VERSION 5.7 ;
BUSBITCHARS "[]" ;
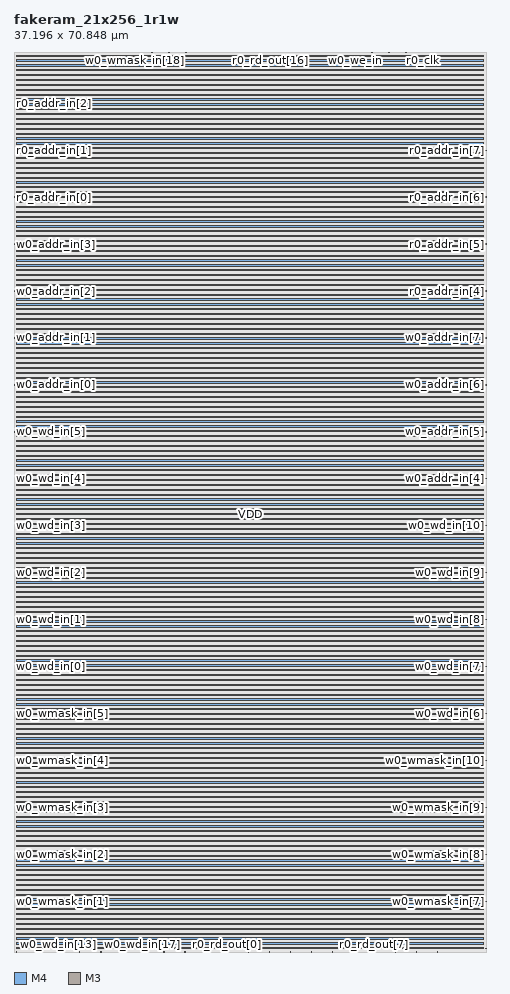
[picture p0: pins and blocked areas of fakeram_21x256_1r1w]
MACRO fakeram_21x256_1r1w
  FOREIGN fakeram_21x256_1r1w 0 0 ;
  SYMMETRY X Y R90 ;
  SIZE 37.196 BY 70.848 ;
  CLASS BLOCK ;
  PIN w0_wmask_in[0]
    DIRECTION INPUT ;
    USE SIGNAL ;
    SHAPE ABUTMENT ;
    PORT
      LAYER M4 ;
      RECT 0.000 0.276 0.072 0.300 ;
    END
  END w0_wmask_in[0]
  PIN w0_wmask_in[1]
    DIRECTION INPUT ;
    USE SIGNAL ;
    SHAPE ABUTMENT ;
    PORT
      LAYER M4 ;
      RECT 0.000 3.972 0.072 3.996 ;
    END
  END w0_wmask_in[1]
  PIN w0_wmask_in[2]
    DIRECTION INPUT ;
    USE SIGNAL ;
    SHAPE ABUTMENT ;
    PORT
      LAYER M4 ;
      RECT 0.000 7.668 0.072 7.692 ;
    END
  END w0_wmask_in[2]
  PIN w0_wmask_in[3]
    DIRECTION INPUT ;
    USE SIGNAL ;
    SHAPE ABUTMENT ;
    PORT
      LAYER M4 ;
      RECT 0.000 11.364 0.072 11.388 ;
    END
  END w0_wmask_in[3]
  PIN w0_wmask_in[4]
    DIRECTION INPUT ;
    USE SIGNAL ;
    SHAPE ABUTMENT ;
    PORT
      LAYER M4 ;
      RECT 0.000 15.060 0.072 15.084 ;
    END
  END w0_wmask_in[4]
  PIN w0_wmask_in[5]
    DIRECTION INPUT ;
    USE SIGNAL ;
    SHAPE ABUTMENT ;
    PORT
      LAYER M4 ;
      RECT 0.000 18.756 0.072 18.780 ;
    END
  END w0_wmask_in[5]
  PIN w0_wmask_in[6]
    DIRECTION INPUT ;
    USE SIGNAL ;
    SHAPE ABUTMENT ;
    PORT
      LAYER M4 ;
      RECT 37.124 0.276 37.196 0.300 ;
    END
  END w0_wmask_in[6]
  PIN w0_wmask_in[7]
    DIRECTION INPUT ;
    USE SIGNAL ;
    SHAPE ABUTMENT ;
    PORT
      LAYER M4 ;
      RECT 37.124 3.972 37.196 3.996 ;
    END
  END w0_wmask_in[7]
  PIN w0_wmask_in[8]
    DIRECTION INPUT ;
    USE SIGNAL ;
    SHAPE ABUTMENT ;
    PORT
      LAYER M4 ;
      RECT 37.124 7.668 37.196 7.692 ;
    END
  END w0_wmask_in[8]
  PIN w0_wmask_in[9]
    DIRECTION INPUT ;
    USE SIGNAL ;
    SHAPE ABUTMENT ;
    PORT
      LAYER M4 ;
      RECT 37.124 11.364 37.196 11.388 ;
    END
  END w0_wmask_in[9]
  PIN w0_wmask_in[10]
    DIRECTION INPUT ;
    USE SIGNAL ;
    SHAPE ABUTMENT ;
    PORT
      LAYER M4 ;
      RECT 37.124 15.060 37.196 15.084 ;
    END
  END w0_wmask_in[10]
  PIN w0_wmask_in[11]
    DIRECTION INPUT ;
    USE SIGNAL ;
    SHAPE ABUTMENT ;
    PORT
      LAYER M3 ;
      RECT 0.207 70.794 0.225 70.848 ;
    END
  END w0_wmask_in[11]
  PIN w0_wmask_in[12]
    DIRECTION INPUT ;
    USE SIGNAL ;
    SHAPE ABUTMENT ;
    PORT
      LAYER M3 ;
      RECT 1.539 70.794 1.557 70.848 ;
    END
  END w0_wmask_in[12]
  PIN w0_wmask_in[13]
    DIRECTION INPUT ;
    USE SIGNAL ;
    SHAPE ABUTMENT ;
    PORT
      LAYER M3 ;
      RECT 2.871 70.794 2.889 70.848 ;
    END
  END w0_wmask_in[13]
  PIN w0_wmask_in[14]
    DIRECTION INPUT ;
    USE SIGNAL ;
    SHAPE ABUTMENT ;
    PORT
      LAYER M3 ;
      RECT 4.203 70.794 4.221 70.848 ;
    END
  END w0_wmask_in[14]
  PIN w0_wmask_in[15]
    DIRECTION INPUT ;
    USE SIGNAL ;
    SHAPE ABUTMENT ;
    PORT
      LAYER M3 ;
      RECT 5.535 70.794 5.553 70.848 ;
    END
  END w0_wmask_in[15]
  PIN w0_wmask_in[16]
    DIRECTION INPUT ;
    USE SIGNAL ;
    SHAPE ABUTMENT ;
    PORT
      LAYER M3 ;
      RECT 6.867 70.794 6.885 70.848 ;
    END
  END w0_wmask_in[16]
  PIN w0_wmask_in[17]
    DIRECTION INPUT ;
    USE SIGNAL ;
    SHAPE ABUTMENT ;
    PORT
      LAYER M3 ;
      RECT 8.199 70.794 8.217 70.848 ;
    END
  END w0_wmask_in[17]
  PIN w0_wmask_in[18]
    DIRECTION INPUT ;
    USE SIGNAL ;
    SHAPE ABUTMENT ;
    PORT
      LAYER M3 ;
      RECT 9.531 70.794 9.549 70.848 ;
    END
  END w0_wmask_in[18]
  PIN w0_wmask_in[19]
    DIRECTION INPUT ;
    USE SIGNAL ;
    SHAPE ABUTMENT ;
    PORT
      LAYER M3 ;
      RECT 10.863 70.794 10.881 70.848 ;
    END
  END w0_wmask_in[19]
  PIN w0_wmask_in[20]
    DIRECTION INPUT ;
    USE SIGNAL ;
    SHAPE ABUTMENT ;
    PORT
      LAYER M3 ;
      RECT 12.195 70.794 12.213 70.848 ;
    END
  END w0_wmask_in[20]
  PIN w0_wd_in[0]
    DIRECTION INPUT ;
    USE SIGNAL ;
    SHAPE ABUTMENT ;
    PORT
      LAYER M4 ;
      RECT 0.000 22.452 0.072 22.476 ;
    END
  END w0_wd_in[0]
  PIN w0_wd_in[1]
    DIRECTION INPUT ;
    USE SIGNAL ;
    SHAPE ABUTMENT ;
    PORT
      LAYER M4 ;
      RECT 0.000 26.148 0.072 26.172 ;
    END
  END w0_wd_in[1]
  PIN w0_wd_in[2]
    DIRECTION INPUT ;
    USE SIGNAL ;
    SHAPE ABUTMENT ;
    PORT
      LAYER M4 ;
      RECT 0.000 29.844 0.072 29.868 ;
    END
  END w0_wd_in[2]
  PIN w0_wd_in[3]
    DIRECTION INPUT ;
    USE SIGNAL ;
    SHAPE ABUTMENT ;
    PORT
      LAYER M4 ;
      RECT 0.000 33.540 0.072 33.564 ;
    END
  END w0_wd_in[3]
  PIN w0_wd_in[4]
    DIRECTION INPUT ;
    USE SIGNAL ;
    SHAPE ABUTMENT ;
    PORT
      LAYER M4 ;
      RECT 0.000 37.236 0.072 37.260 ;
    END
  END w0_wd_in[4]
  PIN w0_wd_in[5]
    DIRECTION INPUT ;
    USE SIGNAL ;
    SHAPE ABUTMENT ;
    PORT
      LAYER M4 ;
      RECT 0.000 40.932 0.072 40.956 ;
    END
  END w0_wd_in[5]
  PIN w0_wd_in[6]
    DIRECTION INPUT ;
    USE SIGNAL ;
    SHAPE ABUTMENT ;
    PORT
      LAYER M4 ;
      RECT 37.124 18.756 37.196 18.780 ;
    END
  END w0_wd_in[6]
  PIN w0_wd_in[7]
    DIRECTION INPUT ;
    USE SIGNAL ;
    SHAPE ABUTMENT ;
    PORT
      LAYER M4 ;
      RECT 37.124 22.452 37.196 22.476 ;
    END
  END w0_wd_in[7]
  PIN w0_wd_in[8]
    DIRECTION INPUT ;
    USE SIGNAL ;
    SHAPE ABUTMENT ;
    PORT
      LAYER M4 ;
      RECT 37.124 26.148 37.196 26.172 ;
    END
  END w0_wd_in[8]
  PIN w0_wd_in[9]
    DIRECTION INPUT ;
    USE SIGNAL ;
    SHAPE ABUTMENT ;
    PORT
      LAYER M4 ;
      RECT 37.124 29.844 37.196 29.868 ;
    END
  END w0_wd_in[9]
  PIN w0_wd_in[10]
    DIRECTION INPUT ;
    USE SIGNAL ;
    SHAPE ABUTMENT ;
    PORT
      LAYER M4 ;
      RECT 37.124 33.540 37.196 33.564 ;
    END
  END w0_wd_in[10]
  PIN w0_wd_in[11]
    DIRECTION INPUT ;
    USE SIGNAL ;
    SHAPE ABUTMENT ;
    PORT
      LAYER M3 ;
      RECT 0.207 0.000 0.225 0.054 ;
    END
  END w0_wd_in[11]
  PIN w0_wd_in[12]
    DIRECTION INPUT ;
    USE SIGNAL ;
    SHAPE ABUTMENT ;
    PORT
      LAYER M3 ;
      RECT 1.863 0.000 1.881 0.054 ;
    END
  END w0_wd_in[12]
  PIN w0_wd_in[13]
    DIRECTION INPUT ;
    USE SIGNAL ;
    SHAPE ABUTMENT ;
    PORT
      LAYER M3 ;
      RECT 3.519 0.000 3.537 0.054 ;
    END
  END w0_wd_in[13]
  PIN w0_wd_in[14]
    DIRECTION INPUT ;
    USE SIGNAL ;
    SHAPE ABUTMENT ;
    PORT
      LAYER M3 ;
      RECT 5.175 0.000 5.193 0.054 ;
    END
  END w0_wd_in[14]
  PIN w0_wd_in[15]
    DIRECTION INPUT ;
    USE SIGNAL ;
    SHAPE ABUTMENT ;
    PORT
      LAYER M3 ;
      RECT 6.831 0.000 6.849 0.054 ;
    END
  END w0_wd_in[15]
  PIN w0_wd_in[16]
    DIRECTION INPUT ;
    USE SIGNAL ;
    SHAPE ABUTMENT ;
    PORT
      LAYER M3 ;
      RECT 8.487 0.000 8.505 0.054 ;
    END
  END w0_wd_in[16]
  PIN w0_wd_in[17]
    DIRECTION INPUT ;
    USE SIGNAL ;
    SHAPE ABUTMENT ;
    PORT
      LAYER M3 ;
      RECT 10.143 0.000 10.161 0.054 ;
    END
  END w0_wd_in[17]
  PIN w0_wd_in[18]
    DIRECTION INPUT ;
    USE SIGNAL ;
    SHAPE ABUTMENT ;
    PORT
      LAYER M3 ;
      RECT 11.799 0.000 11.817 0.054 ;
    END
  END w0_wd_in[18]
  PIN w0_wd_in[19]
    DIRECTION INPUT ;
    USE SIGNAL ;
    SHAPE ABUTMENT ;
    PORT
      LAYER M3 ;
      RECT 13.455 0.000 13.473 0.054 ;
    END
  END w0_wd_in[19]
  PIN w0_wd_in[20]
    DIRECTION INPUT ;
    USE SIGNAL ;
    SHAPE ABUTMENT ;
    PORT
      LAYER M3 ;
      RECT 15.111 0.000 15.129 0.054 ;
    END
  END w0_wd_in[20]
  PIN r0_rd_out[0]
    DIRECTION OUTPUT ;
    USE SIGNAL ;
    SHAPE ABUTMENT ;
    PORT
      LAYER M3 ;
      RECT 16.767 0.000 16.785 0.054 ;
    END
  END r0_rd_out[0]
  PIN r0_rd_out[1]
    DIRECTION OUTPUT ;
    USE SIGNAL ;
    SHAPE ABUTMENT ;
    PORT
      LAYER M3 ;
      RECT 18.423 0.000 18.441 0.054 ;
    END
  END r0_rd_out[1]
  PIN r0_rd_out[2]
    DIRECTION OUTPUT ;
    USE SIGNAL ;
    SHAPE ABUTMENT ;
    PORT
      LAYER M3 ;
      RECT 20.079 0.000 20.097 0.054 ;
    END
  END r0_rd_out[2]
  PIN r0_rd_out[3]
    DIRECTION OUTPUT ;
    USE SIGNAL ;
    SHAPE ABUTMENT ;
    PORT
      LAYER M3 ;
      RECT 21.735 0.000 21.753 0.054 ;
    END
  END r0_rd_out[3]
  PIN r0_rd_out[4]
    DIRECTION OUTPUT ;
    USE SIGNAL ;
    SHAPE ABUTMENT ;
    PORT
      LAYER M3 ;
      RECT 23.391 0.000 23.409 0.054 ;
    END
  END r0_rd_out[4]
  PIN r0_rd_out[5]
    DIRECTION OUTPUT ;
    USE SIGNAL ;
    SHAPE ABUTMENT ;
    PORT
      LAYER M3 ;
      RECT 25.047 0.000 25.065 0.054 ;
    END
  END r0_rd_out[5]
  PIN r0_rd_out[6]
    DIRECTION OUTPUT ;
    USE SIGNAL ;
    SHAPE ABUTMENT ;
    PORT
      LAYER M3 ;
      RECT 26.703 0.000 26.721 0.054 ;
    END
  END r0_rd_out[6]
  PIN r0_rd_out[7]
    DIRECTION OUTPUT ;
    USE SIGNAL ;
    SHAPE ABUTMENT ;
    PORT
      LAYER M3 ;
      RECT 28.359 0.000 28.377 0.054 ;
    END
  END r0_rd_out[7]
  PIN r0_rd_out[8]
    DIRECTION OUTPUT ;
    USE SIGNAL ;
    SHAPE ABUTMENT ;
    PORT
      LAYER M3 ;
      RECT 30.015 0.000 30.033 0.054 ;
    END
  END r0_rd_out[8]
  PIN r0_rd_out[9]
    DIRECTION OUTPUT ;
    USE SIGNAL ;
    SHAPE ABUTMENT ;
    PORT
      LAYER M3 ;
      RECT 31.671 0.000 31.689 0.054 ;
    END
  END r0_rd_out[9]
  PIN r0_rd_out[10]
    DIRECTION OUTPUT ;
    USE SIGNAL ;
    SHAPE ABUTMENT ;
    PORT
      LAYER M3 ;
      RECT 33.327 0.000 33.345 0.054 ;
    END
  END r0_rd_out[10]
  PIN r0_rd_out[11]
    DIRECTION OUTPUT ;
    USE SIGNAL ;
    SHAPE ABUTMENT ;
    PORT
      LAYER M3 ;
      RECT 13.527 70.794 13.545 70.848 ;
    END
  END r0_rd_out[11]
  PIN r0_rd_out[12]
    DIRECTION OUTPUT ;
    USE SIGNAL ;
    SHAPE ABUTMENT ;
    PORT
      LAYER M3 ;
      RECT 14.859 70.794 14.877 70.848 ;
    END
  END r0_rd_out[12]
  PIN r0_rd_out[13]
    DIRECTION OUTPUT ;
    USE SIGNAL ;
    SHAPE ABUTMENT ;
    PORT
      LAYER M3 ;
      RECT 16.191 70.794 16.209 70.848 ;
    END
  END r0_rd_out[13]
  PIN r0_rd_out[14]
    DIRECTION OUTPUT ;
    USE SIGNAL ;
    SHAPE ABUTMENT ;
    PORT
      LAYER M3 ;
      RECT 17.523 70.794 17.541 70.848 ;
    END
  END r0_rd_out[14]
  PIN r0_rd_out[15]
    DIRECTION OUTPUT ;
    USE SIGNAL ;
    SHAPE ABUTMENT ;
    PORT
      LAYER M3 ;
      RECT 18.855 70.794 18.873 70.848 ;
    END
  END r0_rd_out[15]
  PIN r0_rd_out[16]
    DIRECTION OUTPUT ;
    USE SIGNAL ;
    SHAPE ABUTMENT ;
    PORT
      LAYER M3 ;
      RECT 20.187 70.794 20.205 70.848 ;
    END
  END r0_rd_out[16]
  PIN r0_rd_out[17]
    DIRECTION OUTPUT ;
    USE SIGNAL ;
    SHAPE ABUTMENT ;
    PORT
      LAYER M3 ;
      RECT 21.519 70.794 21.537 70.848 ;
    END
  END r0_rd_out[17]
  PIN r0_rd_out[18]
    DIRECTION OUTPUT ;
    USE SIGNAL ;
    SHAPE ABUTMENT ;
    PORT
      LAYER M3 ;
      RECT 22.851 70.794 22.869 70.848 ;
    END
  END r0_rd_out[18]
  PIN r0_rd_out[19]
    DIRECTION OUTPUT ;
    USE SIGNAL ;
    SHAPE ABUTMENT ;
    PORT
      LAYER M3 ;
      RECT 24.183 70.794 24.201 70.848 ;
    END
  END r0_rd_out[19]
  PIN r0_rd_out[20]
    DIRECTION OUTPUT ;
    USE SIGNAL ;
    SHAPE ABUTMENT ;
    PORT
      LAYER M3 ;
      RECT 25.515 70.794 25.533 70.848 ;
    END
  END r0_rd_out[20]
  PIN w0_addr_in[0]
    DIRECTION INPUT ;
    USE SIGNAL ;
    SHAPE ABUTMENT ;
    PORT
      LAYER M4 ;
      RECT 0.000 44.628 0.072 44.652 ;
    END
  END w0_addr_in[0]
  PIN w0_addr_in[1]
    DIRECTION INPUT ;
    USE SIGNAL ;
    SHAPE ABUTMENT ;
    PORT
      LAYER M4 ;
      RECT 0.000 48.324 0.072 48.348 ;
    END
  END w0_addr_in[1]
  PIN w0_addr_in[2]
    DIRECTION INPUT ;
    USE SIGNAL ;
    SHAPE ABUTMENT ;
    PORT
      LAYER M4 ;
      RECT 0.000 52.020 0.072 52.044 ;
    END
  END w0_addr_in[2]
  PIN w0_addr_in[3]
    DIRECTION INPUT ;
    USE SIGNAL ;
    SHAPE ABUTMENT ;
    PORT
      LAYER M4 ;
      RECT 0.000 55.716 0.072 55.740 ;
    END
  END w0_addr_in[3]
  PIN w0_addr_in[4]
    DIRECTION INPUT ;
    USE SIGNAL ;
    SHAPE ABUTMENT ;
    PORT
      LAYER M4 ;
      RECT 37.124 37.236 37.196 37.260 ;
    END
  END w0_addr_in[4]
  PIN w0_addr_in[5]
    DIRECTION INPUT ;
    USE SIGNAL ;
    SHAPE ABUTMENT ;
    PORT
      LAYER M4 ;
      RECT 37.124 40.932 37.196 40.956 ;
    END
  END w0_addr_in[5]
  PIN w0_addr_in[6]
    DIRECTION INPUT ;
    USE SIGNAL ;
    SHAPE ABUTMENT ;
    PORT
      LAYER M4 ;
      RECT 37.124 44.628 37.196 44.652 ;
    END
  END w0_addr_in[6]
  PIN w0_addr_in[7]
    DIRECTION INPUT ;
    USE SIGNAL ;
    SHAPE ABUTMENT ;
    PORT
      LAYER M4 ;
      RECT 37.124 48.324 37.196 48.348 ;
    END
  END w0_addr_in[7]
  PIN r0_addr_in[0]
    DIRECTION INPUT ;
    USE SIGNAL ;
    SHAPE ABUTMENT ;
    PORT
      LAYER M4 ;
      RECT 0.000 59.412 0.072 59.436 ;
    END
  END r0_addr_in[0]
  PIN r0_addr_in[1]
    DIRECTION INPUT ;
    USE SIGNAL ;
    SHAPE ABUTMENT ;
    PORT
      LAYER M4 ;
      RECT 0.000 63.108 0.072 63.132 ;
    END
  END r0_addr_in[1]
  PIN r0_addr_in[2]
    DIRECTION INPUT ;
    USE SIGNAL ;
    SHAPE ABUTMENT ;
    PORT
      LAYER M4 ;
      RECT 0.000 66.804 0.072 66.828 ;
    END
  END r0_addr_in[2]
  PIN r0_addr_in[3]
    DIRECTION INPUT ;
    USE SIGNAL ;
    SHAPE ABUTMENT ;
    PORT
      LAYER M4 ;
      RECT 0.000 70.500 0.072 70.524 ;
    END
  END r0_addr_in[3]
  PIN r0_addr_in[4]
    DIRECTION INPUT ;
    USE SIGNAL ;
    SHAPE ABUTMENT ;
    PORT
      LAYER M4 ;
      RECT 37.124 52.020 37.196 52.044 ;
    END
  END r0_addr_in[4]
  PIN r0_addr_in[5]
    DIRECTION INPUT ;
    USE SIGNAL ;
    SHAPE ABUTMENT ;
    PORT
      LAYER M4 ;
      RECT 37.124 55.716 37.196 55.740 ;
    END
  END r0_addr_in[5]
  PIN r0_addr_in[6]
    DIRECTION INPUT ;
    USE SIGNAL ;
    SHAPE ABUTMENT ;
    PORT
      LAYER M4 ;
      RECT 37.124 59.412 37.196 59.436 ;
    END
  END r0_addr_in[6]
  PIN r0_addr_in[7]
    DIRECTION INPUT ;
    USE SIGNAL ;
    SHAPE ABUTMENT ;
    PORT
      LAYER M4 ;
      RECT 37.124 63.108 37.196 63.132 ;
    END
  END r0_addr_in[7]
  PIN w0_we_in
    DIRECTION INPUT ;
    USE SIGNAL ;
    SHAPE ABUTMENT ;
    PORT
      LAYER M3 ;
      RECT 26.847 70.794 26.865 70.848 ;
    END
  END w0_we_in
  PIN w0_ce_in
    DIRECTION INPUT ;
    USE SIGNAL ;
    SHAPE ABUTMENT ;
    PORT
      LAYER M3 ;
      RECT 28.179 70.794 28.197 70.848 ;
    END
  END w0_ce_in
  PIN w0_clk
    DIRECTION INPUT ;
    USE SIGNAL ;
    SHAPE ABUTMENT ;
    PORT
      LAYER M3 ;
      RECT 29.511 70.794 29.529 70.848 ;
    END
  END w0_clk
  PIN r0_ce_in
    DIRECTION INPUT ;
    USE SIGNAL ;
    SHAPE ABUTMENT ;
    PORT
      LAYER M3 ;
      RECT 30.843 70.794 30.861 70.848 ;
    END
  END r0_ce_in
  PIN r0_clk
    DIRECTION INPUT ;
    USE SIGNAL ;
    SHAPE ABUTMENT ;
    PORT
      LAYER M3 ;
      RECT 32.175 70.794 32.193 70.848 ;
    END
  END r0_clk
  PIN VSS
    DIRECTION INOUT ;
    USE GROUND ;
    PORT
      LAYER M4 ;
      RECT 0.216 0.240 36.980 0.336 ;
      RECT 0.216 1.008 36.980 1.104 ;
      RECT 0.216 1.776 36.980 1.872 ;
      RECT 0.216 2.544 36.980 2.640 ;
      RECT 0.216 3.312 36.980 3.408 ;
      RECT 0.216 4.080 36.980 4.176 ;
      RECT 0.216 4.848 36.980 4.944 ;
      RECT 0.216 5.616 36.980 5.712 ;
      RECT 0.216 6.384 36.980 6.480 ;
      RECT 0.216 7.152 36.980 7.248 ;
      RECT 0.216 7.920 36.980 8.016 ;
      RECT 0.216 8.688 36.980 8.784 ;
      RECT 0.216 9.456 36.980 9.552 ;
      RECT 0.216 10.224 36.980 10.320 ;
      RECT 0.216 10.992 36.980 11.088 ;
      RECT 0.216 11.760 36.980 11.856 ;
      RECT 0.216 12.528 36.980 12.624 ;
      RECT 0.216 13.296 36.980 13.392 ;
      RECT 0.216 14.064 36.980 14.160 ;
      RECT 0.216 14.832 36.980 14.928 ;
      RECT 0.216 15.600 36.980 15.696 ;
      RECT 0.216 16.368 36.980 16.464 ;
      RECT 0.216 17.136 36.980 17.232 ;
      RECT 0.216 17.904 36.980 18.000 ;
      RECT 0.216 18.672 36.980 18.768 ;
      RECT 0.216 19.440 36.980 19.536 ;
      RECT 0.216 20.208 36.980 20.304 ;
      RECT 0.216 20.976 36.980 21.072 ;
      RECT 0.216 21.744 36.980 21.840 ;
      RECT 0.216 22.512 36.980 22.608 ;
      RECT 0.216 23.280 36.980 23.376 ;
      RECT 0.216 24.048 36.980 24.144 ;
      RECT 0.216 24.816 36.980 24.912 ;
      RECT 0.216 25.584 36.980 25.680 ;
      RECT 0.216 26.352 36.980 26.448 ;
      RECT 0.216 27.120 36.980 27.216 ;
      RECT 0.216 27.888 36.980 27.984 ;
      RECT 0.216 28.656 36.980 28.752 ;
      RECT 0.216 29.424 36.980 29.520 ;
      RECT 0.216 30.192 36.980 30.288 ;
      RECT 0.216 30.960 36.980 31.056 ;
      RECT 0.216 31.728 36.980 31.824 ;
      RECT 0.216 32.496 36.980 32.592 ;
      RECT 0.216 33.264 36.980 33.360 ;
      RECT 0.216 34.032 36.980 34.128 ;
      RECT 0.216 34.800 36.980 34.896 ;
      RECT 0.216 35.568 36.980 35.664 ;
      RECT 0.216 36.336 36.980 36.432 ;
      RECT 0.216 37.104 36.980 37.200 ;
      RECT 0.216 37.872 36.980 37.968 ;
      RECT 0.216 38.640 36.980 38.736 ;
      RECT 0.216 39.408 36.980 39.504 ;
      RECT 0.216 40.176 36.980 40.272 ;
      RECT 0.216 40.944 36.980 41.040 ;
      RECT 0.216 41.712 36.980 41.808 ;
      RECT 0.216 42.480 36.980 42.576 ;
      RECT 0.216 43.248 36.980 43.344 ;
      RECT 0.216 44.016 36.980 44.112 ;
      RECT 0.216 44.784 36.980 44.880 ;
      RECT 0.216 45.552 36.980 45.648 ;
      RECT 0.216 46.320 36.980 46.416 ;
      RECT 0.216 47.088 36.980 47.184 ;
      RECT 0.216 47.856 36.980 47.952 ;
      RECT 0.216 48.624 36.980 48.720 ;
      RECT 0.216 49.392 36.980 49.488 ;
      RECT 0.216 50.160 36.980 50.256 ;
      RECT 0.216 50.928 36.980 51.024 ;
      RECT 0.216 51.696 36.980 51.792 ;
      RECT 0.216 52.464 36.980 52.560 ;
      RECT 0.216 53.232 36.980 53.328 ;
      RECT 0.216 54.000 36.980 54.096 ;
      RECT 0.216 54.768 36.980 54.864 ;
      RECT 0.216 55.536 36.980 55.632 ;
      RECT 0.216 56.304 36.980 56.400 ;
      RECT 0.216 57.072 36.980 57.168 ;
      RECT 0.216 57.840 36.980 57.936 ;
      RECT 0.216 58.608 36.980 58.704 ;
      RECT 0.216 59.376 36.980 59.472 ;
      RECT 0.216 60.144 36.980 60.240 ;
      RECT 0.216 60.912 36.980 61.008 ;
      RECT 0.216 61.680 36.980 61.776 ;
      RECT 0.216 62.448 36.980 62.544 ;
      RECT 0.216 63.216 36.980 63.312 ;
      RECT 0.216 63.984 36.980 64.080 ;
      RECT 0.216 64.752 36.980 64.848 ;
      RECT 0.216 65.520 36.980 65.616 ;
      RECT 0.216 66.288 36.980 66.384 ;
      RECT 0.216 67.056 36.980 67.152 ;
      RECT 0.216 67.824 36.980 67.920 ;
      RECT 0.216 68.592 36.980 68.688 ;
      RECT 0.216 69.360 36.980 69.456 ;
      RECT 0.216 70.128 36.980 70.224 ;
    END
  END VSS
  PIN VDD
    DIRECTION INOUT ;
    USE POWER ;
    PORT
      LAYER M4 ;
      RECT 0.216 0.624 36.980 0.720 ;
      RECT 0.216 1.392 36.980 1.488 ;
      RECT 0.216 2.160 36.980 2.256 ;
      RECT 0.216 2.928 36.980 3.024 ;
      RECT 0.216 3.696 36.980 3.792 ;
      RECT 0.216 4.464 36.980 4.560 ;
      RECT 0.216 5.232 36.980 5.328 ;
      RECT 0.216 6.000 36.980 6.096 ;
      RECT 0.216 6.768 36.980 6.864 ;
      RECT 0.216 7.536 36.980 7.632 ;
      RECT 0.216 8.304 36.980 8.400 ;
      RECT 0.216 9.072 36.980 9.168 ;
      RECT 0.216 9.840 36.980 9.936 ;
      RECT 0.216 10.608 36.980 10.704 ;
      RECT 0.216 11.376 36.980 11.472 ;
      RECT 0.216 12.144 36.980 12.240 ;
      RECT 0.216 12.912 36.980 13.008 ;
      RECT 0.216 13.680 36.980 13.776 ;
      RECT 0.216 14.448 36.980 14.544 ;
      RECT 0.216 15.216 36.980 15.312 ;
      RECT 0.216 15.984 36.980 16.080 ;
      RECT 0.216 16.752 36.980 16.848 ;
      RECT 0.216 17.520 36.980 17.616 ;
      RECT 0.216 18.288 36.980 18.384 ;
      RECT 0.216 19.056 36.980 19.152 ;
      RECT 0.216 19.824 36.980 19.920 ;
      RECT 0.216 20.592 36.980 20.688 ;
      RECT 0.216 21.360 36.980 21.456 ;
      RECT 0.216 22.128 36.980 22.224 ;
      RECT 0.216 22.896 36.980 22.992 ;
      RECT 0.216 23.664 36.980 23.760 ;
      RECT 0.216 24.432 36.980 24.528 ;
      RECT 0.216 25.200 36.980 25.296 ;
      RECT 0.216 25.968 36.980 26.064 ;
      RECT 0.216 26.736 36.980 26.832 ;
      RECT 0.216 27.504 36.980 27.600 ;
      RECT 0.216 28.272 36.980 28.368 ;
      RECT 0.216 29.040 36.980 29.136 ;
      RECT 0.216 29.808 36.980 29.904 ;
      RECT 0.216 30.576 36.980 30.672 ;
      RECT 0.216 31.344 36.980 31.440 ;
      RECT 0.216 32.112 36.980 32.208 ;
      RECT 0.216 32.880 36.980 32.976 ;
      RECT 0.216 33.648 36.980 33.744 ;
      RECT 0.216 34.416 36.980 34.512 ;
      RECT 0.216 35.184 36.980 35.280 ;
      RECT 0.216 35.952 36.980 36.048 ;
      RECT 0.216 36.720 36.980 36.816 ;
      RECT 0.216 37.488 36.980 37.584 ;
      RECT 0.216 38.256 36.980 38.352 ;
      RECT 0.216 39.024 36.980 39.120 ;
      RECT 0.216 39.792 36.980 39.888 ;
      RECT 0.216 40.560 36.980 40.656 ;
      RECT 0.216 41.328 36.980 41.424 ;
      RECT 0.216 42.096 36.980 42.192 ;
      RECT 0.216 42.864 36.980 42.960 ;
      RECT 0.216 43.632 36.980 43.728 ;
      RECT 0.216 44.400 36.980 44.496 ;
      RECT 0.216 45.168 36.980 45.264 ;
      RECT 0.216 45.936 36.980 46.032 ;
      RECT 0.216 46.704 36.980 46.800 ;
      RECT 0.216 47.472 36.980 47.568 ;
      RECT 0.216 48.240 36.980 48.336 ;
      RECT 0.216 49.008 36.980 49.104 ;
      RECT 0.216 49.776 36.980 49.872 ;
      RECT 0.216 50.544 36.980 50.640 ;
      RECT 0.216 51.312 36.980 51.408 ;
      RECT 0.216 52.080 36.980 52.176 ;
      RECT 0.216 52.848 36.980 52.944 ;
      RECT 0.216 53.616 36.980 53.712 ;
      RECT 0.216 54.384 36.980 54.480 ;
      RECT 0.216 55.152 36.980 55.248 ;
      RECT 0.216 55.920 36.980 56.016 ;
      RECT 0.216 56.688 36.980 56.784 ;
      RECT 0.216 57.456 36.980 57.552 ;
      RECT 0.216 58.224 36.980 58.320 ;
      RECT 0.216 58.992 36.980 59.088 ;
      RECT 0.216 59.760 36.980 59.856 ;
      RECT 0.216 60.528 36.980 60.624 ;
      RECT 0.216 61.296 36.980 61.392 ;
      RECT 0.216 62.064 36.980 62.160 ;
      RECT 0.216 62.832 36.980 62.928 ;
      RECT 0.216 63.600 36.980 63.696 ;
      RECT 0.216 64.368 36.980 64.464 ;
      RECT 0.216 65.136 36.980 65.232 ;
      RECT 0.216 65.904 36.980 66.000 ;
      RECT 0.216 66.672 36.980 66.768 ;
      RECT 0.216 67.440 36.980 67.536 ;
      RECT 0.216 68.208 36.980 68.304 ;
      RECT 0.216 68.976 36.980 69.072 ;
      RECT 0.216 69.744 36.980 69.840 ;
      RECT 0.216 70.512 36.980 70.608 ;
    END
  END VDD
  OBS
    LAYER M1 ;
    RECT 0 0 37.196 70.848 ;
    LAYER M2 ;
    RECT 0 0 37.196 70.848 ;
    LAYER M3 ;
    RECT 0 0 37.196 70.848 ;
    LAYER M4 ;
    RECT 0 0 37.196 70.848 ;
  END
END fakeram_21x256_1r1w

END LIBRARY
